VERSION 5.8 ;

BUSBITCHARS "[]" ;
DIVIDERCHAR "/" ;

UNITS
  DATABASE MICRONS 1000 ;
END UNITS

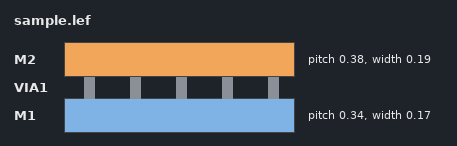
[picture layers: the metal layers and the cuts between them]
LAYER M1
  TYPE ROUTING ;
  PITCH 0.34 ;
  WIDTH 0.17 ;
END M1

LAYER VIA1
  TYPE CUT ;
END VIA1

LAYER M2
  TYPE ROUTING ;
  PITCH 0.38 ;
  WIDTH 0.19 ;
END M2

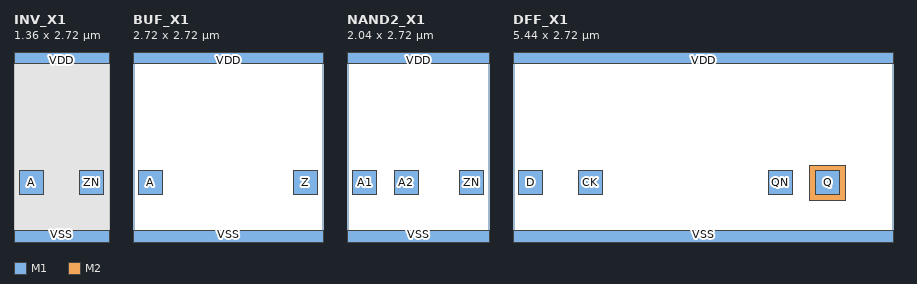
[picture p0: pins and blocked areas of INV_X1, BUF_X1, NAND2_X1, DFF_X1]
MACRO INV_X1
  CLASS CORE ;
  SIZE 1.36 BY 2.72 ;
  ORIGIN 0 0 ;
  PIN A
    DIRECTION INPUT ;
    USE SIGNAL ;
    PORT
      LAYER M1 ;
        RECT 0.085 0.680 0.425 1.020 ;
    END
  END A
  PIN ZN
    DIRECTION OUTPUT ;
    USE SIGNAL ;
    PORT
      LAYER M1 ;
        RECT 0.935 0.680 1.275 1.020 ;
    END
  END ZN
  PIN VDD
    DIRECTION INOUT ;
    USE POWER ;
    PORT
      LAYER M1 ;
        RECT 0.000 2.550 1.360 2.720 ;
    END
  END VDD
  PIN VSS
    DIRECTION INOUT ;
    USE GROUND ;
    PORT
      LAYER M1 ;
        RECT 0.000 0.000 1.360 0.170 ;
    END
  END VSS
  OBS
    LAYER M1 ;
      RECT 0.000 0.170 1.360 2.550 ;
  END
END INV_X1

MACRO BUF_X1
  CLASS CORE ;
  SIZE 2.72 BY 2.72 ;
  ORIGIN 0 0 ;
  PIN A
    DIRECTION INPUT ;
    USE SIGNAL ;
    PORT
      LAYER M1 ;
        RECT 0.085 0.680 0.425 1.020 ;
    END
  END A
  PIN Z
    DIRECTION OUTPUT ;
    USE SIGNAL ;
    PORT
      LAYER M1 ;
        RECT 2.295 0.680 2.635 1.020 ;
    END
  END Z
  PIN VDD
    DIRECTION INOUT ;
    USE POWER ;
    PORT
      LAYER M1 ;
        RECT 0.000 2.550 2.720 2.720 ;
    END
  END VDD
  PIN VSS
    DIRECTION INOUT ;
    USE GROUND ;
    PORT
      LAYER M1 ;
        RECT 0.000 0.000 2.720 0.170 ;
    END
  END VSS
END BUF_X1

MACRO NAND2_X1
  CLASS CORE ;
  SIZE 2.04 BY 2.72 ;
  ORIGIN 0 0 ;
  PIN A1
    DIRECTION INPUT ;
    USE SIGNAL ;
    PORT
      LAYER M1 ;
        RECT 0.085 0.680 0.425 1.020 ;
    END
  END A1
  PIN A2
    DIRECTION INPUT ;
    USE SIGNAL ;
    PORT
      LAYER M1 ;
        RECT 0.680 0.680 1.020 1.020 ;
    END
  END A2
  PIN ZN
    DIRECTION OUTPUT ;
    USE SIGNAL ;
    PORT
      LAYER M1 ;
        RECT 1.615 0.680 1.955 1.020 ;
    END
  END ZN
  PIN VDD
    DIRECTION INOUT ;
    USE POWER ;
    PORT
      LAYER M1 ;
        RECT 0.000 2.550 2.040 2.720 ;
    END
  END VDD
  PIN VSS
    DIRECTION INOUT ;
    USE GROUND ;
    PORT
      LAYER M1 ;
        RECT 0.000 0.000 2.040 0.170 ;
    END
  END VSS
END NAND2_X1

MACRO DFF_X1
  CLASS CORE ;
  SIZE 5.44 BY 2.72 ;
  ORIGIN 0 0 ;
  PIN D
    DIRECTION INPUT ;
    USE SIGNAL ;
    PORT
      LAYER M1 ;
        RECT 0.085 0.680 0.425 1.020 ;
    END
  END D
  PIN CK
    DIRECTION INPUT ;
    USE CLOCK ;
    PORT
      LAYER M1 ;
        RECT 0.935 0.680 1.275 1.020 ;
    END
  END CK
  PIN Q
    DIRECTION OUTPUT ;
    USE SIGNAL ;
    PORT
      LAYER M1 ;
        RECT 4.335 0.680 4.675 1.020 ;
      LAYER M2 ;
        RECT 4.250 0.600 4.760 1.100 ;
    END
  END Q
  PIN QN
    DIRECTION OUTPUT ;
    USE SIGNAL ;
    PORT
      LAYER M1 ;
        RECT 3.655 0.680 3.995 1.020 ;
    END
  END QN
  PIN VDD
    DIRECTION INOUT ;
    USE POWER ;
    PORT
      LAYER M1 ;
        RECT 0.000 2.550 5.440 2.720 ;
    END
  END VDD
  PIN VSS
    DIRECTION INOUT ;
    USE GROUND ;
    PORT
      LAYER M1 ;
        RECT 0.000 0.000 5.440 0.170 ;
    END
  END VSS
END DFF_X1

END LIBRARY
